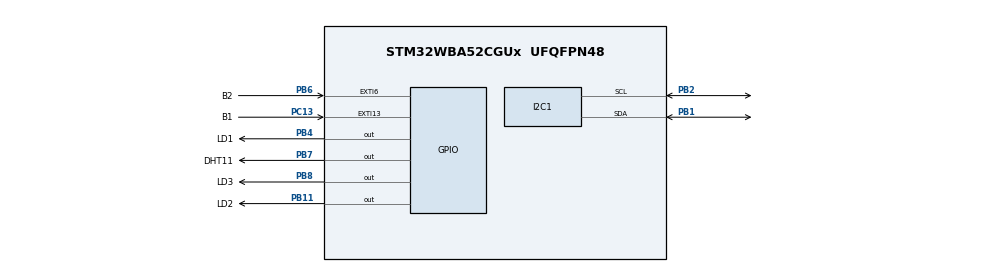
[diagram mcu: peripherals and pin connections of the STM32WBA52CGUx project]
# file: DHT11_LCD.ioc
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CORTEX_M33_NS.userName=CORTEX_M33
I2C1.Timing=0x00C0EAFF
Mcu.Family=STM32WBA
Mcu.Name=STM32WBA52CGUx
Mcu.Package=UFQFPN48
NVIC.EXTI13_IRQn=true\:0\:0\:false\:false\:true\:true\:true\:true
NVIC.EXTI6_IRQn=true\:0\:0\:false\:false\:true\:true\:true\:true
NVIC.PriorityGroup=NVIC_PRIORITYGROUP_4
OSC_IN.GPIO_Label=RCC_OSC_IN
OSC_IN.Mode=HSE-External-Oscillator
OSC_IN.Signal=RCC_OSC_IN
OSC_OUT.GPIO_Label=RCC_OSC_OUT
OSC_OUT.Mode=HSE-External-Oscillator
OSC_OUT.Signal=RCC_OSC_OUT
PA13\ (JTMS/SWDIO).GPIO_Label=DEBUG_JTMS-SWDIO
PA13\ (JTMS/SWDIO).Signal=DEBUG_JTMS-SWDIO
PA14\ (JTCK/SWCLK).GPIO_Label=DEBUG_JTCK-SWCLK
PA14\ (JTCK/SWCLK).Signal=DEBUG_JTCK-SWCLK
PA8.GPIO_Label=USART1_RX
PA8.Signal=USART1_RX
PB1.Mode=I2C
PB1.Signal=I2C1_SDA
PB11.GPIO_Label=LD2
PB11.GPIO_Speed=GPIO_SPEED_FREQ_HIGH
PB11.Signal=GPIO_Output
PB12.GPIO_Label=USART1_TX
PB12.Signal=USART1_TX
PB2.Mode=I2C
PB2.Signal=I2C1_SCL
PB4\ (NJTRST).GPIO_Label=LD1
PB4\ (NJTRST).GPIO_Speed=GPIO_SPEED_FREQ_HIGH
PB4\ (NJTRST).Signal=GPIO_Output
PB6.GPIO_Label=B2
PB6.GPIO_PuPd=GPIO_PULLUP
PB6.Signal=GPXTI6
PB7.GPIO_Label=DHT11
PB7.Signal=GPIO_Output
PB8.GPIO_Label=LD3
PB8.GPIO_Speed=GPIO_SPEED_FREQ_HIGH
PB8.Signal=GPIO_Output
PC13.GPIO_Label=B1
PC13.GPIO_PuPd=GPIO_PULLUP
PC13.Signal=GPXTI13
PC14-OSC32_IN.GPIO_Label=RCC_OSC32_IN
PC14-OSC32_IN.Signal=RCC_OSC32_IN
PC15-OSC32_OUT.GPIO_Label=RCC_OSC32_OUT
PC15-OSC32_OUT.Signal=RCC_OSC32_OUT
ProjectManager.HeapSize=0x200
ProjectManager.StackSize=0x400
ProjectManager.TargetToolchain=STM32CubeIDE
RCC.ADCFreq_Value=50000000
RCC.AHB5CLKDivider=DIV2
RCC.AHBFreq_Value=50000000
RCC.APB1Freq_Value=50000000
RCC.APB1TimFreq_Value=50000000
RCC.APB2Freq_Value=50000000
RCC.APB2TimFreq_Value=50000000
RCC.CortexFreq_Value=6250000
RCC.HCLKFreq_Value=50000000
RCC.HSE_VALUE=32000000
RCC.HSI_VALUE=16000000
RCC.LSE_VALUE=32768
RCC.PLL1R=3
RCC.PLLFRACN=3072
RCC.PLLM=2
RCC.PLLN=9
RCC.PLLSourceVirtual=RCC_PLLSOURCE_HSE
RCC.PWR_Regulator_Voltage_Scale=PWR_REGULATOR_VOLTAGE_SCALE1
RCC.SYSCLKFreq_VALUE=50000000
RCC.SYSCLKSourceVirtual=RCC_SYSCLKSOURCE_PLLCLK
RCC.VCOOutputFreq_Value=150000000
TIM3.Prescaler=64-1
VP_CORTEX_M33_NS_VS_Hclk.Mode=Hclk_Mode
VP_ICACHE_VS_ICACHE.Mode=DirectMappedCache
VP_MEMORYMAP_VS_MEMORYMAP.Mode=CurAppReg
VP_PWR_VS_SECSignals.Mode=Security/Privilege
VP_TIM3_VS_ClockSourceINT.Mode=Internal
board=NUCLEO-WBA52CG

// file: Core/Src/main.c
/* USER CODE BEGIN Header */
/**
  ******************************************************************************
  * @file           : main.c
  * @brief          : Main program body
  ******************************************************************************
  * @attention
  *
  * Copyright (c) 2024 STMicroelectronics.
  * All rights reserved.
  *
  * This software is licensed under terms that can be found in the LICENSE file
  * in the root directory of this software component.
  * If no LICENSE file comes with this software, it is provided AS-IS.
  *
  ******************************************************************************
  */
/* USER CODE END Header */
#include "main.h"
#include "i2c-lcd.h"
#include "stdio.h"
#include"dht11.h"

I2C_HandleTypeDef hi2c1;

TIM_HandleTypeDef htim3;

void SystemClock_Config(void);
static void MX_GPIO_Init(void);
static void MX_ICACHE_Init(void);
static void MX_I2C1_Init(void);
static void MX_TIM3_Init(void);

/* USER CODE BEGIN 0 */
void microDelay (uint16_t delay)
{
  __HAL_TIM_SET_COUNTER(&htim3, 0);
  while (__HAL_TIM_GET_COUNTER(&htim3) < delay);
}

/* USER CODE END 0 */

int main(void)
{

  /* MCU Configuration--------------------------------------------------------*/

  /* Reset of all peripherals, Initializes the Flash interface and the Systick. */
  HAL_Init();

  /* Configure the system clock */
  SystemClock_Config();

  /* Initialize all configured peripherals */
  MX_GPIO_Init();
  MX_ICACHE_Init();
  MX_I2C1_Init();
  MX_TIM3_Init();
  /* USER CODE BEGIN 2 */
  HAL_TIM_Base_Start(&htim3);

  lcd_init();
  lcd_put_cur(0, 0);
  lcd_send_string("installizing...");
  HAL_Delay(2000);
  lcd_clear();

      float tCelsius = 0.0;
      float RH = 0.0;

      while (1) {
          DHT_SCAN(&tCelsius, &RH);

          char str1[16];
          char str2[16];

          lcd_put_cur(0, 0);
          sprintf(str1, "TEMP: %.2f C", tCelsius);
          lcd_send_string(str1);

          lcd_put_cur(1, 0);
          sprintf(str2, "HUMI: %.2f %%", RH);
          lcd_send_string(str2);

          // Read every 2 seconds
          // Assuming a function delay exists
          HAL_Delay(1000);
      }
}

void SystemClock_Config(void)
{
  RCC_OscInitTypeDef RCC_OscInitStruct = {0};
  RCC_ClkInitTypeDef RCC_ClkInitStruct = {0};

  /** Configure the main internal regulator output voltage
  */
  if (HAL_PWREx_ControlVoltageScaling(PWR_REGULATOR_VOLTAGE_SCALE1) != HAL_OK)
  {
    Error_Handler();
  }

  /** Initializes the CPU, AHB and APB busses clocks
  */
  RCC_OscInitStruct.OscillatorType = RCC_OSCILLATORTYPE_HSI;
  RCC_OscInitStruct.HSIState = RCC_HSI_ON;
  RCC_OscInitStruct.HSICalibrationValue = RCC_HSICALIBRATION_DEFAULT;
  RCC_OscInitStruct.PLL1.PLLState = RCC_PLL_ON;
  RCC_OscInitStruct.PLL1.PLLSource = RCC_PLLSOURCE_HSI;
  RCC_OscInitStruct.PLL1.PLLM = 1;
  RCC_OscInitStruct.PLL1.PLLN = 9;
  RCC_OscInitStruct.PLL1.PLLP = 2;
  RCC_OscInitStruct.PLL1.PLLQ = 2;
  RCC_OscInitStruct.PLL1.PLLR = 3;
  RCC_OscInitStruct.PLL1.PLLFractional = 3072;
  if (HAL_RCC_OscConfig(&RCC_OscInitStruct) != HAL_OK)
  {
    Error_Handler();
  }

  /** Initializes the CPU, AHB and APB busses clocks
  */
  RCC_ClkInitStruct.ClockType = RCC_CLOCKTYPE_HCLK|RCC_CLOCKTYPE_SYSCLK
                              |RCC_CLOCKTYPE_PCLK1|RCC_CLOCKTYPE_PCLK2
                              |RCC_CLOCKTYPE_PCLK7|RCC_CLOCKTYPE_HCLK5;
  RCC_ClkInitStruct.SYSCLKSource = RCC_SYSCLKSOURCE_PLLCLK;
  RCC_ClkInitStruct.AHBCLKDivider = RCC_SYSCLK_DIV1;
  RCC_ClkInitStruct.APB1CLKDivider = RCC_HCLK_DIV1;
  RCC_ClkInitStruct.APB2CLKDivider = RCC_HCLK_DIV1;
  RCC_ClkInitStruct.APB7CLKDivider = RCC_HCLK_DIV1;
  RCC_ClkInitStruct.AHB5_PLL1_CLKDivider = RCC_SYSCLK_PLL1_DIV2;
  RCC_ClkInitStruct.AHB5_HSEHSI_CLKDivider = RCC_SYSCLK_HSEHSI_DIV1;

  if (HAL_RCC_ClockConfig(&RCC_ClkInitStruct, FLASH_LATENCY_1) != HAL_OK)
  {
    Error_Handler();
  }
}

static void MX_I2C1_Init(void)
{

  hi2c1.Instance = I2C1;
  hi2c1.Init.Timing = 0x00C0EAFF;
  hi2c1.Init.OwnAddress1 = 0;
  hi2c1.Init.AddressingMode = I2C_ADDRESSINGMODE_7BIT;
  hi2c1.Init.DualAddressMode = I2C_DUALADDRESS_DISABLE;
  hi2c1.Init.OwnAddress2 = 0;
  hi2c1.Init.OwnAddress2Masks = I2C_OA2_NOMASK;
  hi2c1.Init.GeneralCallMode = I2C_GENERALCALL_DISABLE;
  hi2c1.Init.NoStretchMode = I2C_NOSTRETCH_DISABLE;
  if (HAL_I2C_Init(&hi2c1) != HAL_OK)
  {
    Error_Handler();
  }

  /** Configure Analogue filter
  */
  if (HAL_I2CEx_ConfigAnalogFilter(&hi2c1, I2C_ANALOGFILTER_ENABLE) != HAL_OK)
  {
    Error_Handler();
  }

  /** Configure Digital filter
  */
  if (HAL_I2CEx_ConfigDigitalFilter(&hi2c1, 0) != HAL_OK)
  {
    Error_Handler();
  }

}

static void MX_ICACHE_Init(void)
{

  /** Enable instruction cache in 1-way (direct mapped cache)
  */
  if (HAL_ICACHE_ConfigAssociativityMode(ICACHE_1WAY) != HAL_OK)
  {
    Error_Handler();
  }
  if (HAL_ICACHE_Enable() != HAL_OK)
  {
    Error_Handler();
  }

}

static void MX_TIM3_Init(void)
{

  TIM_ClockConfigTypeDef sClockSourceConfig = {0};
  TIM_MasterConfigTypeDef sMasterConfig = {0};

  htim3.Instance = TIM3;
  htim3.Init.Prescaler = 50-1;
  htim3.Init.CounterMode = TIM_COUNTERMODE_UP;
  htim3.Init.Period = 65535;
  htim3.Init.ClockDivision = TIM_CLOCKDIVISION_DIV1;
  htim3.Init.AutoReloadPreload = TIM_AUTORELOAD_PRELOAD_DISABLE;
  if (HAL_TIM_Base_Init(&htim3) != HAL_OK)
  {
    Error_Handler();
  }
  sClockSourceConfig.ClockSource = TIM_CLOCKSOURCE_INTERNAL;
  if (HAL_TIM_ConfigClockSource(&htim3, &sClockSourceConfig) != HAL_OK)
  {
    Error_Handler();
  }
  sMasterConfig.MasterOutputTrigger = TIM_TRGO_RESET;
  sMasterConfig.MasterSlaveMode = TIM_MASTERSLAVEMODE_DISABLE;
  if (HAL_TIMEx_MasterConfigSynchronization(&htim3, &sMasterConfig) != HAL_OK)
  {
    Error_Handler();
  }

}

static void MX_GPIO_Init(void)
{
  GPIO_InitTypeDef GPIO_InitStruct = {0};

  /* GPIO Ports Clock Enable */
  __HAL_RCC_GPIOB_CLK_ENABLE();
  __HAL_RCC_GPIOA_CLK_ENABLE();
  __HAL_RCC_GPIOC_CLK_ENABLE();

  /*Configure GPIO pin Output Level */
  HAL_GPIO_WritePin(GPIOB, LD2_Pin|LD3_Pin|GPIO_PIN_7|LD1_Pin, GPIO_PIN_RESET);

  /*Configure GPIO pin : USART1_TX_Pin */
  GPIO_InitStruct.Pin = USART1_TX_Pin;
  GPIO_InitStruct.Mode = GPIO_MODE_AF_PP;
  GPIO_InitStruct.Pull = GPIO_NOPULL;
  GPIO_InitStruct.Speed = GPIO_SPEED_FREQ_LOW;
  GPIO_InitStruct.Alternate = GPIO_AF7_USART1;
  HAL_GPIO_Init(USART1_TX_GPIO_Port, &GPIO_InitStruct);

  /*Configure GPIO pins : LD2_Pin LD3_Pin LD1_Pin */
  GPIO_InitStruct.Pin = LD2_Pin|LD3_Pin|LD1_Pin;
  GPIO_InitStruct.Mode = GPIO_MODE_OUTPUT_PP;
  GPIO_InitStruct.Pull = GPIO_NOPULL;
  GPIO_InitStruct.Speed = GPIO_SPEED_FREQ_HIGH;
  HAL_GPIO_Init(GPIOB, &GPIO_InitStruct);

  /*Configure GPIO pin : USART1_RX_Pin */
  GPIO_InitStruct.Pin = USART1_RX_Pin;
  GPIO_InitStruct.Mode = GPIO_MODE_AF_PP;
  GPIO_InitStruct.Pull = GPIO_NOPULL;
  GPIO_InitStruct.Speed = GPIO_SPEED_FREQ_LOW;
  GPIO_InitStruct.Alternate = GPIO_AF7_USART1;
  HAL_GPIO_Init(USART1_RX_GPIO_Port, &GPIO_InitStruct);

  /*Configure GPIO pin : B1_Pin */
  GPIO_InitStruct.Pin = B1_Pin;
  GPIO_InitStruct.Mode = GPIO_MODE_IT_RISING;
  GPIO_InitStruct.Pull = GPIO_PULLUP;
  HAL_GPIO_Init(B1_GPIO_Port, &GPIO_InitStruct);

  /*Configure GPIO pin : PB7 */
  GPIO_InitStruct.Pin = GPIO_PIN_7;
  GPIO_InitStruct.Mode = GPIO_MODE_OUTPUT_PP;
  GPIO_InitStruct.Pull = GPIO_PULLUP;
  GPIO_InitStruct.Speed = GPIO_SPEED_FREQ_LOW;
  HAL_GPIO_Init(GPIOB, &GPIO_InitStruct);

  /*Configure GPIO pin : B2_Pin */
  GPIO_InitStruct.Pin = B2_Pin;
  GPIO_InitStruct.Mode = GPIO_MODE_IT_RISING;
  GPIO_InitStruct.Pull = GPIO_PULLUP;
  HAL_GPIO_Init(B2_GPIO_Port, &GPIO_InitStruct);

  /* EXTI interrupt init*/
  HAL_NVIC_SetPriority(EXTI6_IRQn, 0, 0);
  HAL_NVIC_EnableIRQ(EXTI6_IRQn);

  HAL_NVIC_SetPriority(EXTI13_IRQn, 0, 0);
  HAL_NVIC_EnableIRQ(EXTI13_IRQn);

}

void Error_Handler(void)
{
  __disable_irq();
  while (1)
  {
  }
}
